# Minimal 3-routing-layer tech for the stacked-via enclosure tests.
#
# V12 carries a width-conditioned LEF58_ENCLOSURE on its ABOVE (MET2) side:
# below 0.300 um of MET2 the cuts need 0.000 x 0.055 of overhang, at or above
# 0.300 um they need 0.050 x 0.050.  V23 has no width tier, but its MET2 pad is
# 0.320 um tall, so a MET1 -> MET3 stack pushes the merged MET2 metal over the
# V12 threshold.  See The-OpenROAD-Project/OpenROAD#11129.
VERSION 5.8 ;
BUSBITCHARS "[]" ;
DIVIDERCHAR "/" ;
UNITS
  DATABASE MICRONS 1000 ;
END UNITS
MANUFACTURINGGRID 0.005 ;
SITE core
  CLASS CORE ;
  SIZE 0.2 BY 1.6 ;
END core
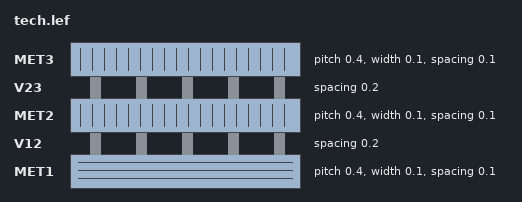
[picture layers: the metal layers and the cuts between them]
LAYER MET1
  TYPE ROUTING ;
  DIRECTION HORIZONTAL ;
  PITCH 0.4 ;
  WIDTH 0.1 ;
  SPACING 0.1 ;
END MET1
LAYER V12
  TYPE CUT ;
  SPACING 0.2 ;
  PROPERTY LEF58_CUTCLASS "CUTCLASS VA WIDTH 0.140 ;" ;
  PROPERTY LEF58_ENCLOSURE "ENCLOSURE CUTCLASS VA ABOVE 0.000 0.055 ;
    ENCLOSURE CUTCLASS VA ABOVE 0.050 0.050 WIDTH 0.300 ;
    ENCLOSURE CUTCLASS VA BELOW 0.020 0.020 ;" ;
END V12
LAYER MET2
  TYPE ROUTING ;
  DIRECTION VERTICAL ;
  PITCH 0.4 ;
  WIDTH 0.1 ;
  SPACING 0.1 ;
END MET2
LAYER V23
  TYPE CUT ;
  SPACING 0.2 ;
  PROPERTY LEF58_CUTCLASS "CUTCLASS VB WIDTH 0.140 ;" ;
  PROPERTY LEF58_ENCLOSURE "ENCLOSURE CUTCLASS VB BELOW 0.000 0.090 ;
    ENCLOSURE CUTCLASS VB ABOVE 0.020 0.020 ;" ;
END V23
LAYER MET3
  TYPE ROUTING ;
  DIRECTION VERTICAL ;
  PITCH 0.4 ;
  WIDTH 0.1 ;
  SPACING 0.1 ;
END MET3
VIARULE V12_GEN GENERATE
  LAYER MET1 ;
    ENCLOSURE 0.020 0.020 ;
  LAYER MET2 ;
    ENCLOSURE 0.000 0.055 ;
  LAYER V12 ;
    RECT -0.070 -0.070 0.070 0.070 ;
    SPACING 0.340 BY 0.340 ;
END V12_GEN
VIARULE V23_GEN GENERATE
  LAYER MET2 ;
    ENCLOSURE 0.000 0.090 ;
  LAYER MET3 ;
    ENCLOSURE 0.020 0.020 ;
  LAYER V23 ;
    RECT -0.070 -0.070 0.070 0.070 ;
    SPACING 0.340 BY 0.340 ;
END V23_GEN
END LIBRARY
